# Generated by FakeRAM 2.0
VERSION 5.7 ;
BUSBITCHARS "[]" ;
PROPERTYDEFINITIONS
  MACRO width INTEGER ;
  MACRO depth INTEGER ;
  MACRO banks INTEGER ;
END PROPERTYDEFINITIONS
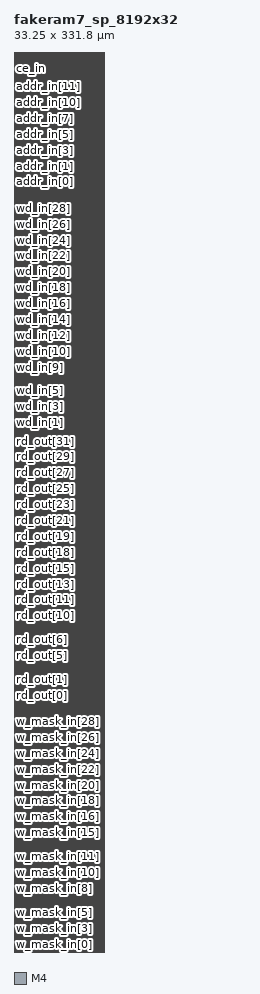
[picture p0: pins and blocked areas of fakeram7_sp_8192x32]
MACRO fakeram7_sp_8192x32
  PROPERTY width 32 ;
  PROPERTY depth 8192 ;
  PROPERTY banks 8 ;
  FOREIGN fakeram7_sp_8192x32 0 0 ;
  SYMMETRY X Y ;
  SIZE 33.250 BY 331.800 ;
  CLASS BLOCK ;
  PIN w_mask_in[0]
    DIRECTION INPUT ;
    USE SIGNAL ;
    SHAPE ABUTMENT ;
    PORT
      LAYER M4 ;
      RECT 0.000 0.048 0.024 0.072 ;
    END
  END w_mask_in[0]
  PIN w_mask_in[1]
    DIRECTION INPUT ;
    USE SIGNAL ;
    SHAPE ABUTMENT ;
    PORT
      LAYER M4 ;
      RECT 0.000 2.976 0.024 3.000 ;
    END
  END w_mask_in[1]
  PIN w_mask_in[2]
    DIRECTION INPUT ;
    USE SIGNAL ;
    SHAPE ABUTMENT ;
    PORT
      LAYER M4 ;
      RECT 0.000 5.904 0.024 5.928 ;
    END
  END w_mask_in[2]
  PIN w_mask_in[3]
    DIRECTION INPUT ;
    USE SIGNAL ;
    SHAPE ABUTMENT ;
    PORT
      LAYER M4 ;
      RECT 0.000 8.832 0.024 8.856 ;
    END
  END w_mask_in[3]
  PIN w_mask_in[4]
    DIRECTION INPUT ;
    USE SIGNAL ;
    SHAPE ABUTMENT ;
    PORT
      LAYER M4 ;
      RECT 0.000 11.760 0.024 11.784 ;
    END
  END w_mask_in[4]
  PIN w_mask_in[5]
    DIRECTION INPUT ;
    USE SIGNAL ;
    SHAPE ABUTMENT ;
    PORT
      LAYER M4 ;
      RECT 0.000 14.688 0.024 14.712 ;
    END
  END w_mask_in[5]
  PIN w_mask_in[6]
    DIRECTION INPUT ;
    USE SIGNAL ;
    SHAPE ABUTMENT ;
    PORT
      LAYER M4 ;
      RECT 0.000 17.616 0.024 17.640 ;
    END
  END w_mask_in[6]
  PIN w_mask_in[7]
    DIRECTION INPUT ;
    USE SIGNAL ;
    SHAPE ABUTMENT ;
    PORT
      LAYER M4 ;
      RECT 0.000 20.544 0.024 20.568 ;
    END
  END w_mask_in[7]
  PIN w_mask_in[8]
    DIRECTION INPUT ;
    USE SIGNAL ;
    SHAPE ABUTMENT ;
    PORT
      LAYER M4 ;
      RECT 0.000 23.472 0.024 23.496 ;
    END
  END w_mask_in[8]
  PIN w_mask_in[9]
    DIRECTION INPUT ;
    USE SIGNAL ;
    SHAPE ABUTMENT ;
    PORT
      LAYER M4 ;
      RECT 0.000 26.400 0.024 26.424 ;
    END
  END w_mask_in[9]
  PIN w_mask_in[10]
    DIRECTION INPUT ;
    USE SIGNAL ;
    SHAPE ABUTMENT ;
    PORT
      LAYER M4 ;
      RECT 0.000 29.328 0.024 29.352 ;
    END
  END w_mask_in[10]
  PIN w_mask_in[11]
    DIRECTION INPUT ;
    USE SIGNAL ;
    SHAPE ABUTMENT ;
    PORT
      LAYER M4 ;
      RECT 0.000 32.256 0.024 32.280 ;
    END
  END w_mask_in[11]
  PIN w_mask_in[12]
    DIRECTION INPUT ;
    USE SIGNAL ;
    SHAPE ABUTMENT ;
    PORT
      LAYER M4 ;
      RECT 0.000 35.184 0.024 35.208 ;
    END
  END w_mask_in[12]
  PIN w_mask_in[13]
    DIRECTION INPUT ;
    USE SIGNAL ;
    SHAPE ABUTMENT ;
    PORT
      LAYER M4 ;
      RECT 0.000 38.112 0.024 38.136 ;
    END
  END w_mask_in[13]
  PIN w_mask_in[14]
    DIRECTION INPUT ;
    USE SIGNAL ;
    SHAPE ABUTMENT ;
    PORT
      LAYER M4 ;
      RECT 0.000 41.040 0.024 41.064 ;
    END
  END w_mask_in[14]
  PIN w_mask_in[15]
    DIRECTION INPUT ;
    USE SIGNAL ;
    SHAPE ABUTMENT ;
    PORT
      LAYER M4 ;
      RECT 0.000 43.968 0.024 43.992 ;
    END
  END w_mask_in[15]
  PIN w_mask_in[16]
    DIRECTION INPUT ;
    USE SIGNAL ;
    SHAPE ABUTMENT ;
    PORT
      LAYER M4 ;
      RECT 0.000 46.896 0.024 46.920 ;
    END
  END w_mask_in[16]
  PIN w_mask_in[17]
    DIRECTION INPUT ;
    USE SIGNAL ;
    SHAPE ABUTMENT ;
    PORT
      LAYER M4 ;
      RECT 0.000 49.824 0.024 49.848 ;
    END
  END w_mask_in[17]
  PIN w_mask_in[18]
    DIRECTION INPUT ;
    USE SIGNAL ;
    SHAPE ABUTMENT ;
    PORT
      LAYER M4 ;
      RECT 0.000 52.752 0.024 52.776 ;
    END
  END w_mask_in[18]
  PIN w_mask_in[19]
    DIRECTION INPUT ;
    USE SIGNAL ;
    SHAPE ABUTMENT ;
    PORT
      LAYER M4 ;
      RECT 0.000 55.680 0.024 55.704 ;
    END
  END w_mask_in[19]
  PIN w_mask_in[20]
    DIRECTION INPUT ;
    USE SIGNAL ;
    SHAPE ABUTMENT ;
    PORT
      LAYER M4 ;
      RECT 0.000 58.608 0.024 58.632 ;
    END
  END w_mask_in[20]
  PIN w_mask_in[21]
    DIRECTION INPUT ;
    USE SIGNAL ;
    SHAPE ABUTMENT ;
    PORT
      LAYER M4 ;
      RECT 0.000 61.536 0.024 61.560 ;
    END
  END w_mask_in[21]
  PIN w_mask_in[22]
    DIRECTION INPUT ;
    USE SIGNAL ;
    SHAPE ABUTMENT ;
    PORT
      LAYER M4 ;
      RECT 0.000 64.464 0.024 64.488 ;
    END
  END w_mask_in[22]
  PIN w_mask_in[23]
    DIRECTION INPUT ;
    USE SIGNAL ;
    SHAPE ABUTMENT ;
    PORT
      LAYER M4 ;
      RECT 0.000 67.392 0.024 67.416 ;
    END
  END w_mask_in[23]
  PIN w_mask_in[24]
    DIRECTION INPUT ;
    USE SIGNAL ;
    SHAPE ABUTMENT ;
    PORT
      LAYER M4 ;
      RECT 0.000 70.320 0.024 70.344 ;
    END
  END w_mask_in[24]
  PIN w_mask_in[25]
    DIRECTION INPUT ;
    USE SIGNAL ;
    SHAPE ABUTMENT ;
    PORT
      LAYER M4 ;
      RECT 0.000 73.248 0.024 73.272 ;
    END
  END w_mask_in[25]
  PIN w_mask_in[26]
    DIRECTION INPUT ;
    USE SIGNAL ;
    SHAPE ABUTMENT ;
    PORT
      LAYER M4 ;
      RECT 0.000 76.176 0.024 76.200 ;
    END
  END w_mask_in[26]
  PIN w_mask_in[27]
    DIRECTION INPUT ;
    USE SIGNAL ;
    SHAPE ABUTMENT ;
    PORT
      LAYER M4 ;
      RECT 0.000 79.104 0.024 79.128 ;
    END
  END w_mask_in[27]
  PIN w_mask_in[28]
    DIRECTION INPUT ;
    USE SIGNAL ;
    SHAPE ABUTMENT ;
    PORT
      LAYER M4 ;
      RECT 0.000 82.032 0.024 82.056 ;
    END
  END w_mask_in[28]
  PIN w_mask_in[29]
    DIRECTION INPUT ;
    USE SIGNAL ;
    SHAPE ABUTMENT ;
    PORT
      LAYER M4 ;
      RECT 0.000 84.960 0.024 84.984 ;
    END
  END w_mask_in[29]
  PIN w_mask_in[30]
    DIRECTION INPUT ;
    USE SIGNAL ;
    SHAPE ABUTMENT ;
    PORT
      LAYER M4 ;
      RECT 0.000 87.888 0.024 87.912 ;
    END
  END w_mask_in[30]
  PIN w_mask_in[31]
    DIRECTION INPUT ;
    USE SIGNAL ;
    SHAPE ABUTMENT ;
    PORT
      LAYER M4 ;
      RECT 0.000 90.816 0.024 90.840 ;
    END
  END w_mask_in[31]
  PIN rd_out[0]
    DIRECTION OUTPUT ;
    USE SIGNAL ;
    SHAPE ABUTMENT ;
    PORT
      LAYER M4 ;
      RECT 0.000 94.656 0.024 94.680 ;
    END
  END rd_out[0]
  PIN rd_out[1]
    DIRECTION OUTPUT ;
    USE SIGNAL ;
    SHAPE ABUTMENT ;
    PORT
      LAYER M4 ;
      RECT 0.000 97.584 0.024 97.608 ;
    END
  END rd_out[1]
  PIN rd_out[2]
    DIRECTION OUTPUT ;
    USE SIGNAL ;
    SHAPE ABUTMENT ;
    PORT
      LAYER M4 ;
      RECT 0.000 100.512 0.024 100.536 ;
    END
  END rd_out[2]
  PIN rd_out[3]
    DIRECTION OUTPUT ;
    USE SIGNAL ;
    SHAPE ABUTMENT ;
    PORT
      LAYER M4 ;
      RECT 0.000 103.440 0.024 103.464 ;
    END
  END rd_out[3]
  PIN rd_out[4]
    DIRECTION OUTPUT ;
    USE SIGNAL ;
    SHAPE ABUTMENT ;
    PORT
      LAYER M4 ;
      RECT 0.000 106.368 0.024 106.392 ;
    END
  END rd_out[4]
  PIN rd_out[5]
    DIRECTION OUTPUT ;
    USE SIGNAL ;
    SHAPE ABUTMENT ;
    PORT
      LAYER M4 ;
      RECT 0.000 109.296 0.024 109.320 ;
    END
  END rd_out[5]
  PIN rd_out[6]
    DIRECTION OUTPUT ;
    USE SIGNAL ;
    SHAPE ABUTMENT ;
    PORT
      LAYER M4 ;
      RECT 0.000 112.224 0.024 112.248 ;
    END
  END rd_out[6]
  PIN rd_out[7]
    DIRECTION OUTPUT ;
    USE SIGNAL ;
    SHAPE ABUTMENT ;
    PORT
      LAYER M4 ;
      RECT 0.000 115.152 0.024 115.176 ;
    END
  END rd_out[7]
  PIN rd_out[8]
    DIRECTION OUTPUT ;
    USE SIGNAL ;
    SHAPE ABUTMENT ;
    PORT
      LAYER M4 ;
      RECT 0.000 118.080 0.024 118.104 ;
    END
  END rd_out[8]
  PIN rd_out[9]
    DIRECTION OUTPUT ;
    USE SIGNAL ;
    SHAPE ABUTMENT ;
    PORT
      LAYER M4 ;
      RECT 0.000 121.008 0.024 121.032 ;
    END
  END rd_out[9]
  PIN rd_out[10]
    DIRECTION OUTPUT ;
    USE SIGNAL ;
    SHAPE ABUTMENT ;
    PORT
      LAYER M4 ;
      RECT 0.000 123.936 0.024 123.960 ;
    END
  END rd_out[10]
  PIN rd_out[11]
    DIRECTION OUTPUT ;
    USE SIGNAL ;
    SHAPE ABUTMENT ;
    PORT
      LAYER M4 ;
      RECT 0.000 126.864 0.024 126.888 ;
    END
  END rd_out[11]
  PIN rd_out[12]
    DIRECTION OUTPUT ;
    USE SIGNAL ;
    SHAPE ABUTMENT ;
    PORT
      LAYER M4 ;
      RECT 0.000 129.792 0.024 129.816 ;
    END
  END rd_out[12]
  PIN rd_out[13]
    DIRECTION OUTPUT ;
    USE SIGNAL ;
    SHAPE ABUTMENT ;
    PORT
      LAYER M4 ;
      RECT 0.000 132.720 0.024 132.744 ;
    END
  END rd_out[13]
  PIN rd_out[14]
    DIRECTION OUTPUT ;
    USE SIGNAL ;
    SHAPE ABUTMENT ;
    PORT
      LAYER M4 ;
      RECT 0.000 135.648 0.024 135.672 ;
    END
  END rd_out[14]
  PIN rd_out[15]
    DIRECTION OUTPUT ;
    USE SIGNAL ;
    SHAPE ABUTMENT ;
    PORT
      LAYER M4 ;
      RECT 0.000 138.576 0.024 138.600 ;
    END
  END rd_out[15]
  PIN rd_out[16]
    DIRECTION OUTPUT ;
    USE SIGNAL ;
    SHAPE ABUTMENT ;
    PORT
      LAYER M4 ;
      RECT 0.000 141.504 0.024 141.528 ;
    END
  END rd_out[16]
  PIN rd_out[17]
    DIRECTION OUTPUT ;
    USE SIGNAL ;
    SHAPE ABUTMENT ;
    PORT
      LAYER M4 ;
      RECT 0.000 144.432 0.024 144.456 ;
    END
  END rd_out[17]
  PIN rd_out[18]
    DIRECTION OUTPUT ;
    USE SIGNAL ;
    SHAPE ABUTMENT ;
    PORT
      LAYER M4 ;
      RECT 0.000 147.360 0.024 147.384 ;
    END
  END rd_out[18]
  PIN rd_out[19]
    DIRECTION OUTPUT ;
    USE SIGNAL ;
    SHAPE ABUTMENT ;
    PORT
      LAYER M4 ;
      RECT 0.000 150.288 0.024 150.312 ;
    END
  END rd_out[19]
  PIN rd_out[20]
    DIRECTION OUTPUT ;
    USE SIGNAL ;
    SHAPE ABUTMENT ;
    PORT
      LAYER M4 ;
      RECT 0.000 153.216 0.024 153.240 ;
    END
  END rd_out[20]
  PIN rd_out[21]
    DIRECTION OUTPUT ;
    USE SIGNAL ;
    SHAPE ABUTMENT ;
    PORT
      LAYER M4 ;
      RECT 0.000 156.144 0.024 156.168 ;
    END
  END rd_out[21]
  PIN rd_out[22]
    DIRECTION OUTPUT ;
    USE SIGNAL ;
    SHAPE ABUTMENT ;
    PORT
      LAYER M4 ;
      RECT 0.000 159.072 0.024 159.096 ;
    END
  END rd_out[22]
  PIN rd_out[23]
    DIRECTION OUTPUT ;
    USE SIGNAL ;
    SHAPE ABUTMENT ;
    PORT
      LAYER M4 ;
      RECT 0.000 162.000 0.024 162.024 ;
    END
  END rd_out[23]
  PIN rd_out[24]
    DIRECTION OUTPUT ;
    USE SIGNAL ;
    SHAPE ABUTMENT ;
    PORT
      LAYER M4 ;
      RECT 0.000 164.928 0.024 164.952 ;
    END
  END rd_out[24]
  PIN rd_out[25]
    DIRECTION OUTPUT ;
    USE SIGNAL ;
    SHAPE ABUTMENT ;
    PORT
      LAYER M4 ;
      RECT 0.000 167.856 0.024 167.880 ;
    END
  END rd_out[25]
  PIN rd_out[26]
    DIRECTION OUTPUT ;
    USE SIGNAL ;
    SHAPE ABUTMENT ;
    PORT
      LAYER M4 ;
      RECT 0.000 170.784 0.024 170.808 ;
    END
  END rd_out[26]
  PIN rd_out[27]
    DIRECTION OUTPUT ;
    USE SIGNAL ;
    SHAPE ABUTMENT ;
    PORT
      LAYER M4 ;
      RECT 0.000 173.712 0.024 173.736 ;
    END
  END rd_out[27]
  PIN rd_out[28]
    DIRECTION OUTPUT ;
    USE SIGNAL ;
    SHAPE ABUTMENT ;
    PORT
      LAYER M4 ;
      RECT 0.000 176.640 0.024 176.664 ;
    END
  END rd_out[28]
  PIN rd_out[29]
    DIRECTION OUTPUT ;
    USE SIGNAL ;
    SHAPE ABUTMENT ;
    PORT
      LAYER M4 ;
      RECT 0.000 179.568 0.024 179.592 ;
    END
  END rd_out[29]
  PIN rd_out[30]
    DIRECTION OUTPUT ;
    USE SIGNAL ;
    SHAPE ABUTMENT ;
    PORT
      LAYER M4 ;
      RECT 0.000 182.496 0.024 182.520 ;
    END
  END rd_out[30]
  PIN rd_out[31]
    DIRECTION OUTPUT ;
    USE SIGNAL ;
    SHAPE ABUTMENT ;
    PORT
      LAYER M4 ;
      RECT 0.000 185.424 0.024 185.448 ;
    END
  END rd_out[31]
  PIN wd_in[0]
    DIRECTION INPUT ;
    USE SIGNAL ;
    SHAPE ABUTMENT ;
    PORT
      LAYER M4 ;
      RECT 0.000 189.264 0.024 189.288 ;
    END
  END wd_in[0]
  PIN wd_in[1]
    DIRECTION INPUT ;
    USE SIGNAL ;
    SHAPE ABUTMENT ;
    PORT
      LAYER M4 ;
      RECT 0.000 192.192 0.024 192.216 ;
    END
  END wd_in[1]
  PIN wd_in[2]
    DIRECTION INPUT ;
    USE SIGNAL ;
    SHAPE ABUTMENT ;
    PORT
      LAYER M4 ;
      RECT 0.000 195.120 0.024 195.144 ;
    END
  END wd_in[2]
  PIN wd_in[3]
    DIRECTION INPUT ;
    USE SIGNAL ;
    SHAPE ABUTMENT ;
    PORT
      LAYER M4 ;
      RECT 0.000 198.048 0.024 198.072 ;
    END
  END wd_in[3]
  PIN wd_in[4]
    DIRECTION INPUT ;
    USE SIGNAL ;
    SHAPE ABUTMENT ;
    PORT
      LAYER M4 ;
      RECT 0.000 200.976 0.024 201.000 ;
    END
  END wd_in[4]
  PIN wd_in[5]
    DIRECTION INPUT ;
    USE SIGNAL ;
    SHAPE ABUTMENT ;
    PORT
      LAYER M4 ;
      RECT 0.000 203.904 0.024 203.928 ;
    END
  END wd_in[5]
  PIN wd_in[6]
    DIRECTION INPUT ;
    USE SIGNAL ;
    SHAPE ABUTMENT ;
    PORT
      LAYER M4 ;
      RECT 0.000 206.832 0.024 206.856 ;
    END
  END wd_in[6]
  PIN wd_in[7]
    DIRECTION INPUT ;
    USE SIGNAL ;
    SHAPE ABUTMENT ;
    PORT
      LAYER M4 ;
      RECT 0.000 209.760 0.024 209.784 ;
    END
  END wd_in[7]
  PIN wd_in[8]
    DIRECTION INPUT ;
    USE SIGNAL ;
    SHAPE ABUTMENT ;
    PORT
      LAYER M4 ;
      RECT 0.000 212.688 0.024 212.712 ;
    END
  END wd_in[8]
  PIN wd_in[9]
    DIRECTION INPUT ;
    USE SIGNAL ;
    SHAPE ABUTMENT ;
    PORT
      LAYER M4 ;
      RECT 0.000 215.616 0.024 215.640 ;
    END
  END wd_in[9]
  PIN wd_in[10]
    DIRECTION INPUT ;
    USE SIGNAL ;
    SHAPE ABUTMENT ;
    PORT
      LAYER M4 ;
      RECT 0.000 218.544 0.024 218.568 ;
    END
  END wd_in[10]
  PIN wd_in[11]
    DIRECTION INPUT ;
    USE SIGNAL ;
    SHAPE ABUTMENT ;
    PORT
      LAYER M4 ;
      RECT 0.000 221.472 0.024 221.496 ;
    END
  END wd_in[11]
  PIN wd_in[12]
    DIRECTION INPUT ;
    USE SIGNAL ;
    SHAPE ABUTMENT ;
    PORT
      LAYER M4 ;
      RECT 0.000 224.400 0.024 224.424 ;
    END
  END wd_in[12]
  PIN wd_in[13]
    DIRECTION INPUT ;
    USE SIGNAL ;
    SHAPE ABUTMENT ;
    PORT
      LAYER M4 ;
      RECT 0.000 227.328 0.024 227.352 ;
    END
  END wd_in[13]
  PIN wd_in[14]
    DIRECTION INPUT ;
    USE SIGNAL ;
    SHAPE ABUTMENT ;
    PORT
      LAYER M4 ;
      RECT 0.000 230.256 0.024 230.280 ;
    END
  END wd_in[14]
  PIN wd_in[15]
    DIRECTION INPUT ;
    USE SIGNAL ;
    SHAPE ABUTMENT ;
    PORT
      LAYER M4 ;
      RECT 0.000 233.184 0.024 233.208 ;
    END
  END wd_in[15]
  PIN wd_in[16]
    DIRECTION INPUT ;
    USE SIGNAL ;
    SHAPE ABUTMENT ;
    PORT
      LAYER M4 ;
      RECT 0.000 236.112 0.024 236.136 ;
    END
  END wd_in[16]
  PIN wd_in[17]
    DIRECTION INPUT ;
    USE SIGNAL ;
    SHAPE ABUTMENT ;
    PORT
      LAYER M4 ;
      RECT 0.000 239.040 0.024 239.064 ;
    END
  END wd_in[17]
  PIN wd_in[18]
    DIRECTION INPUT ;
    USE SIGNAL ;
    SHAPE ABUTMENT ;
    PORT
      LAYER M4 ;
      RECT 0.000 241.968 0.024 241.992 ;
    END
  END wd_in[18]
  PIN wd_in[19]
    DIRECTION INPUT ;
    USE SIGNAL ;
    SHAPE ABUTMENT ;
    PORT
      LAYER M4 ;
      RECT 0.000 244.896 0.024 244.920 ;
    END
  END wd_in[19]
  PIN wd_in[20]
    DIRECTION INPUT ;
    USE SIGNAL ;
    SHAPE ABUTMENT ;
    PORT
      LAYER M4 ;
      RECT 0.000 247.824 0.024 247.848 ;
    END
  END wd_in[20]
  PIN wd_in[21]
    DIRECTION INPUT ;
    USE SIGNAL ;
    SHAPE ABUTMENT ;
    PORT
      LAYER M4 ;
      RECT 0.000 250.752 0.024 250.776 ;
    END
  END wd_in[21]
  PIN wd_in[22]
    DIRECTION INPUT ;
    USE SIGNAL ;
    SHAPE ABUTMENT ;
    PORT
      LAYER M4 ;
      RECT 0.000 253.680 0.024 253.704 ;
    END
  END wd_in[22]
  PIN wd_in[23]
    DIRECTION INPUT ;
    USE SIGNAL ;
    SHAPE ABUTMENT ;
    PORT
      LAYER M4 ;
      RECT 0.000 256.608 0.024 256.632 ;
    END
  END wd_in[23]
  PIN wd_in[24]
    DIRECTION INPUT ;
    USE SIGNAL ;
    SHAPE ABUTMENT ;
    PORT
      LAYER M4 ;
      RECT 0.000 259.536 0.024 259.560 ;
    END
  END wd_in[24]
  PIN wd_in[25]
    DIRECTION INPUT ;
    USE SIGNAL ;
    SHAPE ABUTMENT ;
    PORT
      LAYER M4 ;
      RECT 0.000 262.464 0.024 262.488 ;
    END
  END wd_in[25]
  PIN wd_in[26]
    DIRECTION INPUT ;
    USE SIGNAL ;
    SHAPE ABUTMENT ;
    PORT
      LAYER M4 ;
      RECT 0.000 265.392 0.024 265.416 ;
    END
  END wd_in[26]
  PIN wd_in[27]
    DIRECTION INPUT ;
    USE SIGNAL ;
    SHAPE ABUTMENT ;
    PORT
      LAYER M4 ;
      RECT 0.000 268.320 0.024 268.344 ;
    END
  END wd_in[27]
  PIN wd_in[28]
    DIRECTION INPUT ;
    USE SIGNAL ;
    SHAPE ABUTMENT ;
    PORT
      LAYER M4 ;
      RECT 0.000 271.248 0.024 271.272 ;
    END
  END wd_in[28]
  PIN wd_in[29]
    DIRECTION INPUT ;
    USE SIGNAL ;
    SHAPE ABUTMENT ;
    PORT
      LAYER M4 ;
      RECT 0.000 274.176 0.024 274.200 ;
    END
  END wd_in[29]
  PIN wd_in[30]
    DIRECTION INPUT ;
    USE SIGNAL ;
    SHAPE ABUTMENT ;
    PORT
      LAYER M4 ;
      RECT 0.000 277.104 0.024 277.128 ;
    END
  END wd_in[30]
  PIN wd_in[31]
    DIRECTION INPUT ;
    USE SIGNAL ;
    SHAPE ABUTMENT ;
    PORT
      LAYER M4 ;
      RECT 0.000 280.032 0.024 280.056 ;
    END
  END wd_in[31]
  PIN addr_in[0]
    DIRECTION INPUT ;
    USE SIGNAL ;
    SHAPE ABUTMENT ;
    PORT
      LAYER M4 ;
      RECT 0.000 283.872 0.024 283.896 ;
    END
  END addr_in[0]
  PIN addr_in[1]
    DIRECTION INPUT ;
    USE SIGNAL ;
    SHAPE ABUTMENT ;
    PORT
      LAYER M4 ;
      RECT 0.000 286.800 0.024 286.824 ;
    END
  END addr_in[1]
  PIN addr_in[2]
    DIRECTION INPUT ;
    USE SIGNAL ;
    SHAPE ABUTMENT ;
    PORT
      LAYER M4 ;
      RECT 0.000 289.728 0.024 289.752 ;
    END
  END addr_in[2]
  PIN addr_in[3]
    DIRECTION INPUT ;
    USE SIGNAL ;
    SHAPE ABUTMENT ;
    PORT
      LAYER M4 ;
      RECT 0.000 292.656 0.024 292.680 ;
    END
  END addr_in[3]
  PIN addr_in[4]
    DIRECTION INPUT ;
    USE SIGNAL ;
    SHAPE ABUTMENT ;
    PORT
      LAYER M4 ;
      RECT 0.000 295.584 0.024 295.608 ;
    END
  END addr_in[4]
  PIN addr_in[5]
    DIRECTION INPUT ;
    USE SIGNAL ;
    SHAPE ABUTMENT ;
    PORT
      LAYER M4 ;
      RECT 0.000 298.512 0.024 298.536 ;
    END
  END addr_in[5]
  PIN addr_in[6]
    DIRECTION INPUT ;
    USE SIGNAL ;
    SHAPE ABUTMENT ;
    PORT
      LAYER M4 ;
      RECT 0.000 301.440 0.024 301.464 ;
    END
  END addr_in[6]
  PIN addr_in[7]
    DIRECTION INPUT ;
    USE SIGNAL ;
    SHAPE ABUTMENT ;
    PORT
      LAYER M4 ;
      RECT 0.000 304.368 0.024 304.392 ;
    END
  END addr_in[7]
  PIN addr_in[8]
    DIRECTION INPUT ;
    USE SIGNAL ;
    SHAPE ABUTMENT ;
    PORT
      LAYER M4 ;
      RECT 0.000 307.296 0.024 307.320 ;
    END
  END addr_in[8]
  PIN addr_in[9]
    DIRECTION INPUT ;
    USE SIGNAL ;
    SHAPE ABUTMENT ;
    PORT
      LAYER M4 ;
      RECT 0.000 310.224 0.024 310.248 ;
    END
  END addr_in[9]
  PIN addr_in[10]
    DIRECTION INPUT ;
    USE SIGNAL ;
    SHAPE ABUTMENT ;
    PORT
      LAYER M4 ;
      RECT 0.000 313.152 0.024 313.176 ;
    END
  END addr_in[10]
  PIN addr_in[11]
    DIRECTION INPUT ;
    USE SIGNAL ;
    SHAPE ABUTMENT ;
    PORT
      LAYER M4 ;
      RECT 0.000 316.080 0.024 316.104 ;
    END
  END addr_in[11]
  PIN addr_in[12]
    DIRECTION INPUT ;
    USE SIGNAL ;
    SHAPE ABUTMENT ;
    PORT
      LAYER M4 ;
      RECT 0.000 319.008 0.024 319.032 ;
    END
  END addr_in[12]
  PIN we_in
    DIRECTION INPUT ;
    USE SIGNAL ;
    SHAPE ABUTMENT ;
    PORT
      LAYER M4 ;
      RECT 0.000 322.848 0.024 322.872 ;
    END
  END we_in
  PIN ce_in
    DIRECTION INPUT ;
    USE SIGNAL ;
    SHAPE ABUTMENT ;
    PORT
      LAYER M4 ;
      RECT 0.000 325.776 0.024 325.800 ;
    END
  END ce_in
  PIN clk
    DIRECTION INPUT ;
    USE SIGNAL ;
    SHAPE ABUTMENT ;
    PORT
      LAYER M4 ;
      RECT 0.000 328.704 0.024 328.728 ;
    END
  END clk
  PIN VSS
    DIRECTION INOUT ;
    USE GROUND ;
    PORT
      LAYER M4 ;
      RECT 0.048 0.000 33.202 0.096 ;
      RECT 0.048 0.768 33.202 0.864 ;
      RECT 0.048 1.536 33.202 1.632 ;
      RECT 0.048 2.304 33.202 2.400 ;
      RECT 0.048 3.072 33.202 3.168 ;
      RECT 0.048 3.840 33.202 3.936 ;
      RECT 0.048 4.608 33.202 4.704 ;
      RECT 0.048 5.376 33.202 5.472 ;
      RECT 0.048 6.144 33.202 6.240 ;
      RECT 0.048 6.912 33.202 7.008 ;
      RECT 0.048 7.680 33.202 7.776 ;
      RECT 0.048 8.448 33.202 8.544 ;
      RECT 0.048 9.216 33.202 9.312 ;
      RECT 0.048 9.984 33.202 10.080 ;
      RECT 0.048 10.752 33.202 10.848 ;
      RECT 0.048 11.520 33.202 11.616 ;
      RECT 0.048 12.288 33.202 12.384 ;
      RECT 0.048 13.056 33.202 13.152 ;
      RECT 0.048 13.824 33.202 13.920 ;
      RECT 0.048 14.592 33.202 14.688 ;
      RECT 0.048 15.360 33.202 15.456 ;
      RECT 0.048 16.128 33.202 16.224 ;
      RECT 0.048 16.896 33.202 16.992 ;
      RECT 0.048 17.664 33.202 17.760 ;
      RECT 0.048 18.432 33.202 18.528 ;
      RECT 0.048 19.200 33.202 19.296 ;
      RECT 0.048 19.968 33.202 20.064 ;
      RECT 0.048 20.736 33.202 20.832 ;
      RECT 0.048 21.504 33.202 21.600 ;
      RECT 0.048 22.272 33.202 22.368 ;
      RECT 0.048 23.040 33.202 23.136 ;
      RECT 0.048 23.808 33.202 23.904 ;
      RECT 0.048 24.576 33.202 24.672 ;
      RECT 0.048 25.344 33.202 25.440 ;
      RECT 0.048 26.112 33.202 26.208 ;
      RECT 0.048 26.880 33.202 26.976 ;
      RECT 0.048 27.648 33.202 27.744 ;
      RECT 0.048 28.416 33.202 28.512 ;
      RECT 0.048 29.184 33.202 29.280 ;
      RECT 0.048 29.952 33.202 30.048 ;
      RECT 0.048 30.720 33.202 30.816 ;
      RECT 0.048 31.488 33.202 31.584 ;
      RECT 0.048 32.256 33.202 32.352 ;
      RECT 0.048 33.024 33.202 33.120 ;
      RECT 0.048 33.792 33.202 33.888 ;
      RECT 0.048 34.560 33.202 34.656 ;
      RECT 0.048 35.328 33.202 35.424 ;
      RECT 0.048 36.096 33.202 36.192 ;
      RECT 0.048 36.864 33.202 36.960 ;
      RECT 0.048 37.632 33.202 37.728 ;
      RECT 0.048 38.400 33.202 38.496 ;
      RECT 0.048 39.168 33.202 39.264 ;
      RECT 0.048 39.936 33.202 40.032 ;
      RECT 0.048 40.704 33.202 40.800 ;
      RECT 0.048 41.472 33.202 41.568 ;
      RECT 0.048 42.240 33.202 42.336 ;
      RECT 0.048 43.008 33.202 43.104 ;
      RECT 0.048 43.776 33.202 43.872 ;
      RECT 0.048 44.544 33.202 44.640 ;
      RECT 0.048 45.312 33.202 45.408 ;
      RECT 0.048 46.080 33.202 46.176 ;
      RECT 0.048 46.848 33.202 46.944 ;
      RECT 0.048 47.616 33.202 47.712 ;
      RECT 0.048 48.384 33.202 48.480 ;
      RECT 0.048 49.152 33.202 49.248 ;
      RECT 0.048 49.920 33.202 50.016 ;
      RECT 0.048 50.688 33.202 50.784 ;
      RECT 0.048 51.456 33.202 51.552 ;
      RECT 0.048 52.224 33.202 52.320 ;
      RECT 0.048 52.992 33.202 53.088 ;
      RECT 0.048 53.760 33.202 53.856 ;
      RECT 0.048 54.528 33.202 54.624 ;
      RECT 0.048 55.296 33.202 55.392 ;
      RECT 0.048 56.064 33.202 56.160 ;
      RECT 0.048 56.832 33.202 56.928 ;
      RECT 0.048 57.600 33.202 57.696 ;
      RECT 0.048 58.368 33.202 58.464 ;
      RECT 0.048 59.136 33.202 59.232 ;
      RECT 0.048 59.904 33.202 60.000 ;
      RECT 0.048 60.672 33.202 60.768 ;
      RECT 0.048 61.440 33.202 61.536 ;
      RECT 0.048 62.208 33.202 62.304 ;
      RECT 0.048 62.976 33.202 63.072 ;
      RECT 0.048 63.744 33.202 63.840 ;
      RECT 0.048 64.512 33.202 64.608 ;
      RECT 0.048 65.280 33.202 65.376 ;
      RECT 0.048 66.048 33.202 66.144 ;
      RECT 0.048 66.816 33.202 66.912 ;
      RECT 0.048 67.584 33.202 67.680 ;
      RECT 0.048 68.352 33.202 68.448 ;
      RECT 0.048 69.120 33.202 69.216 ;
      RECT 0.048 69.888 33.202 69.984 ;
      RECT 0.048 70.656 33.202 70.752 ;
      RECT 0.048 71.424 33.202 71.520 ;
      RECT 0.048 72.192 33.202 72.288 ;
      RECT 0.048 72.960 33.202 73.056 ;
      RECT 0.048 73.728 33.202 73.824 ;
      RECT 0.048 74.496 33.202 74.592 ;
      RECT 0.048 75.264 33.202 75.360 ;
      RECT 0.048 76.032 33.202 76.128 ;
      RECT 0.048 76.800 33.202 76.896 ;
      RECT 0.048 77.568 33.202 77.664 ;
      RECT 0.048 78.336 33.202 78.432 ;
      RECT 0.048 79.104 33.202 79.200 ;
      RECT 0.048 79.872 33.202 79.968 ;
      RECT 0.048 80.640 33.202 80.736 ;
      RECT 0.048 81.408 33.202 81.504 ;
      RECT 0.048 82.176 33.202 82.272 ;
      RECT 0.048 82.944 33.202 83.040 ;
      RECT 0.048 83.712 33.202 83.808 ;
      RECT 0.048 84.480 33.202 84.576 ;
      RECT 0.048 85.248 33.202 85.344 ;
      RECT 0.048 86.016 33.202 86.112 ;
      RECT 0.048 86.784 33.202 86.880 ;
      RECT 0.048 87.552 33.202 87.648 ;
      RECT 0.048 88.320 33.202 88.416 ;
      RECT 0.048 89.088 33.202 89.184 ;
      RECT 0.048 89.856 33.202 89.952 ;
      RECT 0.048 90.624 33.202 90.720 ;
      RECT 0.048 91.392 33.202 91.488 ;
      RECT 0.048 92.160 33.202 92.256 ;
      RECT 0.048 92.928 33.202 93.024 ;
      RECT 0.048 93.696 33.202 93.792 ;
      RECT 0.048 94.464 33.202 94.560 ;
      RECT 0.048 95.232 33.202 95.328 ;
      RECT 0.048 96.000 33.202 96.096 ;
      RECT 0.048 96.768 33.202 96.864 ;
      RECT 0.048 97.536 33.202 97.632 ;
      RECT 0.048 98.304 33.202 98.400 ;
      RECT 0.048 99.072 33.202 99.168 ;
      RECT 0.048 99.840 33.202 99.936 ;
      RECT 0.048 100.608 33.202 100.704 ;
      RECT 0.048 101.376 33.202 101.472 ;
      RECT 0.048 102.144 33.202 102.240 ;
      RECT 0.048 102.912 33.202 103.008 ;
      RECT 0.048 103.680 33.202 103.776 ;
      RECT 0.048 104.448 33.202 104.544 ;
      RECT 0.048 105.216 33.202 105.312 ;
      RECT 0.048 105.984 33.202 106.080 ;
      RECT 0.048 106.752 33.202 106.848 ;
      RECT 0.048 107.520 33.202 107.616 ;
      RECT 0.048 108.288 33.202 108.384 ;
      RECT 0.048 109.056 33.202 109.152 ;
      RECT 0.048 109.824 33.202 109.920 ;
      RECT 0.048 110.592 33.202 110.688 ;
      RECT 0.048 111.360 33.202 111.456 ;
      RECT 0.048 112.128 33.202 112.224 ;
      RECT 0.048 112.896 33.202 112.992 ;
      RECT 0.048 113.664 33.202 113.760 ;
      RECT 0.048 114.432 33.202 114.528 ;
      RECT 0.048 115.200 33.202 115.296 ;
      RECT 0.048 115.968 33.202 116.064 ;
      RECT 0.048 116.736 33.202 116.832 ;
      RECT 0.048 117.504 33.202 117.600 ;
      RECT 0.048 118.272 33.202 118.368 ;
      RECT 0.048 119.040 33.202 119.136 ;
      RECT 0.048 119.808 33.202 119.904 ;
      RECT 0.048 120.576 33.202 120.672 ;
      RECT 0.048 121.344 33.202 121.440 ;
      RECT 0.048 122.112 33.202 122.208 ;
      RECT 0.048 122.880 33.202 122.976 ;
      RECT 0.048 123.648 33.202 123.744 ;
      RECT 0.048 124.416 33.202 124.512 ;
      RECT 0.048 125.184 33.202 125.280 ;
      RECT 0.048 125.952 33.202 126.048 ;
      RECT 0.048 126.720 33.202 126.816 ;
      RECT 0.048 127.488 33.202 127.584 ;
      RECT 0.048 128.256 33.202 128.352 ;
      RECT 0.048 129.024 33.202 129.120 ;
      RECT 0.048 129.792 33.202 129.888 ;
      RECT 0.048 130.560 33.202 130.656 ;
      RECT 0.048 131.328 33.202 131.424 ;
      RECT 0.048 132.096 33.202 132.192 ;
      RECT 0.048 132.864 33.202 132.960 ;
      RECT 0.048 133.632 33.202 133.728 ;
      RECT 0.048 134.400 33.202 134.496 ;
      RECT 0.048 135.168 33.202 135.264 ;
      RECT 0.048 135.936 33.202 136.032 ;
      RECT 0.048 136.704 33.202 136.800 ;
      RECT 0.048 137.472 33.202 137.568 ;
      RECT 0.048 138.240 33.202 138.336 ;
      RECT 0.048 139.008 33.202 139.104 ;
      RECT 0.048 139.776 33.202 139.872 ;
      RECT 0.048 140.544 33.202 140.640 ;
      RECT 0.048 141.312 33.202 141.408 ;
      RECT 0.048 142.080 33.202 142.176 ;
      RECT 0.048 142.848 33.202 142.944 ;
      RECT 0.048 143.616 33.202 143.712 ;
      RECT 0.048 144.384 33.202 144.480 ;
      RECT 0.048 145.152 33.202 145.248 ;
      RECT 0.048 145.920 33.202 146.016 ;
      RECT 0.048 146.688 33.202 146.784 ;
      RECT 0.048 147.456 33.202 147.552 ;
      RECT 0.048 148.224 33.202 148.320 ;
      RECT 0.048 148.992 33.202 149.088 ;
      RECT 0.048 149.760 33.202 149.856 ;
      RECT 0.048 150.528 33.202 150.624 ;
      RECT 0.048 151.296 33.202 151.392 ;
      RECT 0.048 152.064 33.202 152.160 ;
      RECT 0.048 152.832 33.202 152.928 ;
      RECT 0.048 153.600 33.202 153.696 ;
      RECT 0.048 154.368 33.202 154.464 ;
      RECT 0.048 155.136 33.202 155.232 ;
      RECT 0.048 155.904 33.202 156.000 ;
      RECT 0.048 156.672 33.202 156.768 ;
      RECT 0.048 157.440 33.202 157.536 ;
      RECT 0.048 158.208 33.202 158.304 ;
      RECT 0.048 158.976 33.202 159.072 ;
      RECT 0.048 159.744 33.202 159.840 ;
      RECT 0.048 160.512 33.202 160.608 ;
      RECT 0.048 161.280 33.202 161.376 ;
      RECT 0.048 162.048 33.202 162.144 ;
      RECT 0.048 162.816 33.202 162.912 ;
      RECT 0.048 163.584 33.202 163.680 ;
      RECT 0.048 164.352 33.202 164.448 ;
      RECT 0.048 165.120 33.202 165.216 ;
      RECT 0.048 165.888 33.202 165.984 ;
      RECT 0.048 166.656 33.202 166.752 ;
      RECT 0.048 167.424 33.202 167.520 ;
      RECT 0.048 168.192 33.202 168.288 ;
      RECT 0.048 168.960 33.202 169.056 ;
      RECT 0.048 169.728 33.202 169.824 ;
      RECT 0.048 170.496 33.202 170.592 ;
      RECT 0.048 171.264 33.202 171.360 ;
      RECT 0.048 172.032 33.202 172.128 ;
      RECT 0.048 172.800 33.202 172.896 ;
      RECT 0.048 173.568 33.202 173.664 ;
      RECT 0.048 174.336 33.202 174.432 ;
      RECT 0.048 175.104 33.202 175.200 ;
      RECT 0.048 175.872 33.202 175.968 ;
      RECT 0.048 176.640 33.202 176.736 ;
      RECT 0.048 177.408 33.202 177.504 ;
      RECT 0.048 178.176 33.202 178.272 ;
      RECT 0.048 178.944 33.202 179.040 ;
      RECT 0.048 179.712 33.202 179.808 ;
      RECT 0.048 180.480 33.202 180.576 ;
      RECT 0.048 181.248 33.202 181.344 ;
      RECT 0.048 182.016 33.202 182.112 ;
      RECT 0.048 182.784 33.202 182.880 ;
      RECT 0.048 183.552 33.202 183.648 ;
      RECT 0.048 184.320 33.202 184.416 ;
      RECT 0.048 185.088 33.202 185.184 ;
      RECT 0.048 185.856 33.202 185.952 ;
      RECT 0.048 186.624 33.202 186.720 ;
      RECT 0.048 187.392 33.202 187.488 ;
      RECT 0.048 188.160 33.202 188.256 ;
      RECT 0.048 188.928 33.202 189.024 ;
      RECT 0.048 189.696 33.202 189.792 ;
      RECT 0.048 190.464 33.202 190.560 ;
      RECT 0.048 191.232 33.202 191.328 ;
      RECT 0.048 192.000 33.202 192.096 ;
      RECT 0.048 192.768 33.202 192.864 ;
      RECT 0.048 193.536 33.202 193.632 ;
      RECT 0.048 194.304 33.202 194.400 ;
      RECT 0.048 195.072 33.202 195.168 ;
      RECT 0.048 195.840 33.202 195.936 ;
      RECT 0.048 196.608 33.202 196.704 ;
      RECT 0.048 197.376 33.202 197.472 ;
      RECT 0.048 198.144 33.202 198.240 ;
      RECT 0.048 198.912 33.202 199.008 ;
      RECT 0.048 199.680 33.202 199.776 ;
      RECT 0.048 200.448 33.202 200.544 ;
      RECT 0.048 201.216 33.202 201.312 ;
      RECT 0.048 201.984 33.202 202.080 ;
      RECT 0.048 202.752 33.202 202.848 ;
      RECT 0.048 203.520 33.202 203.616 ;
      RECT 0.048 204.288 33.202 204.384 ;
      RECT 0.048 205.056 33.202 205.152 ;
      RECT 0.048 205.824 33.202 205.920 ;
      RECT 0.048 206.592 33.202 206.688 ;
      RECT 0.048 207.360 33.202 207.456 ;
      RECT 0.048 208.128 33.202 208.224 ;
      RECT 0.048 208.896 33.202 208.992 ;
      RECT 0.048 209.664 33.202 209.760 ;
      RECT 0.048 210.432 33.202 210.528 ;
      RECT 0.048 211.200 33.202 211.296 ;
      RECT 0.048 211.968 33.202 212.064 ;
      RECT 0.048 212.736 33.202 212.832 ;
      RECT 0.048 213.504 33.202 213.600 ;
      RECT 0.048 214.272 33.202 214.368 ;
      RECT 0.048 215.040 33.202 215.136 ;
      RECT 0.048 215.808 33.202 215.904 ;
      RECT 0.048 216.576 33.202 216.672 ;
      RECT 0.048 217.344 33.202 217.440 ;
      RECT 0.048 218.112 33.202 218.208 ;
      RECT 0.048 218.880 33.202 218.976 ;
      RECT 0.048 219.648 33.202 219.744 ;
      RECT 0.048 220.416 33.202 220.512 ;
      RECT 0.048 221.184 33.202 221.280 ;
      RECT 0.048 221.952 33.202 222.048 ;
      RECT 0.048 222.720 33.202 222.816 ;
      RECT 0.048 223.488 33.202 223.584 ;
      RECT 0.048 224.256 33.202 224.352 ;
      RECT 0.048 225.024 33.202 225.120 ;
      RECT 0.048 225.792 33.202 225.888 ;
      RECT 0.048 226.560 33.202 226.656 ;
      RECT 0.048 227.328 33.202 227.424 ;
      RECT 0.048 228.096 33.202 228.192 ;
      RECT 0.048 228.864 33.202 228.960 ;
      RECT 0.048 229.632 33.202 229.728 ;
      RECT 0.048 230.400 33.202 230.496 ;
      RECT 0.048 231.168 33.202 231.264 ;
      RECT 0.048 231.936 33.202 232.032 ;
      RECT 0.048 232.704 33.202 232.800 ;
      RECT 0.048 233.472 33.202 233.568 ;
      RECT 0.048 234.240 33.202 234.336 ;
      RECT 0.048 235.008 33.202 235.104 ;
      RECT 0.048 235.776 33.202 235.872 ;
      RECT 0.048 236.544 33.202 236.640 ;
      RECT 0.048 237.312 33.202 237.408 ;
      RECT 0.048 238.080 33.202 238.176 ;
      RECT 0.048 238.848 33.202 238.944 ;
      RECT 0.048 239.616 33.202 239.712 ;
      RECT 0.048 240.384 33.202 240.480 ;
      RECT 0.048 241.152 33.202 241.248 ;
      RECT 0.048 241.920 33.202 242.016 ;
      RECT 0.048 242.688 33.202 242.784 ;
      RECT 0.048 243.456 33.202 243.552 ;
      RECT 0.048 244.224 33.202 244.320 ;
      RECT 0.048 244.992 33.202 245.088 ;
      RECT 0.048 245.760 33.202 245.856 ;
      RECT 0.048 246.528 33.202 246.624 ;
      RECT 0.048 247.296 33.202 247.392 ;
      RECT 0.048 248.064 33.202 248.160 ;
      RECT 0.048 248.832 33.202 248.928 ;
      RECT 0.048 249.600 33.202 249.696 ;
      RECT 0.048 250.368 33.202 250.464 ;
      RECT 0.048 251.136 33.202 251.232 ;
      RECT 0.048 251.904 33.202 252.000 ;
      RECT 0.048 252.672 33.202 252.768 ;
      RECT 0.048 253.440 33.202 253.536 ;
      RECT 0.048 254.208 33.202 254.304 ;
      RECT 0.048 254.976 33.202 255.072 ;
      RECT 0.048 255.744 33.202 255.840 ;
      RECT 0.048 256.512 33.202 256.608 ;
      RECT 0.048 257.280 33.202 257.376 ;
      RECT 0.048 258.048 33.202 258.144 ;
      RECT 0.048 258.816 33.202 258.912 ;
      RECT 0.048 259.584 33.202 259.680 ;
      RECT 0.048 260.352 33.202 260.448 ;
      RECT 0.048 261.120 33.202 261.216 ;
      RECT 0.048 261.888 33.202 261.984 ;
      RECT 0.048 262.656 33.202 262.752 ;
      RECT 0.048 263.424 33.202 263.520 ;
      RECT 0.048 264.192 33.202 264.288 ;
      RECT 0.048 264.960 33.202 265.056 ;
      RECT 0.048 265.728 33.202 265.824 ;
      RECT 0.048 266.496 33.202 266.592 ;
      RECT 0.048 267.264 33.202 267.360 ;
      RECT 0.048 268.032 33.202 268.128 ;
      RECT 0.048 268.800 33.202 268.896 ;
      RECT 0.048 269.568 33.202 269.664 ;
      RECT 0.048 270.336 33.202 270.432 ;
      RECT 0.048 271.104 33.202 271.200 ;
      RECT 0.048 271.872 33.202 271.968 ;
      RECT 0.048 272.640 33.202 272.736 ;
      RECT 0.048 273.408 33.202 273.504 ;
      RECT 0.048 274.176 33.202 274.272 ;
      RECT 0.048 274.944 33.202 275.040 ;
      RECT 0.048 275.712 33.202 275.808 ;
      RECT 0.048 276.480 33.202 276.576 ;
      RECT 0.048 277.248 33.202 277.344 ;
      RECT 0.048 278.016 33.202 278.112 ;
      RECT 0.048 278.784 33.202 278.880 ;
      RECT 0.048 279.552 33.202 279.648 ;
      RECT 0.048 280.320 33.202 280.416 ;
      RECT 0.048 281.088 33.202 281.184 ;
      RECT 0.048 281.856 33.202 281.952 ;
      RECT 0.048 282.624 33.202 282.720 ;
      RECT 0.048 283.392 33.202 283.488 ;
      RECT 0.048 284.160 33.202 284.256 ;
      RECT 0.048 284.928 33.202 285.024 ;
      RECT 0.048 285.696 33.202 285.792 ;
      RECT 0.048 286.464 33.202 286.560 ;
      RECT 0.048 287.232 33.202 287.328 ;
      RECT 0.048 288.000 33.202 288.096 ;
      RECT 0.048 288.768 33.202 288.864 ;
      RECT 0.048 289.536 33.202 289.632 ;
      RECT 0.048 290.304 33.202 290.400 ;
      RECT 0.048 291.072 33.202 291.168 ;
      RECT 0.048 291.840 33.202 291.936 ;
      RECT 0.048 292.608 33.202 292.704 ;
      RECT 0.048 293.376 33.202 293.472 ;
      RECT 0.048 294.144 33.202 294.240 ;
      RECT 0.048 294.912 33.202 295.008 ;
      RECT 0.048 295.680 33.202 295.776 ;
      RECT 0.048 296.448 33.202 296.544 ;
      RECT 0.048 297.216 33.202 297.312 ;
      RECT 0.048 297.984 33.202 298.080 ;
      RECT 0.048 298.752 33.202 298.848 ;
      RECT 0.048 299.520 33.202 299.616 ;
      RECT 0.048 300.288 33.202 300.384 ;
      RECT 0.048 301.056 33.202 301.152 ;
      RECT 0.048 301.824 33.202 301.920 ;
      RECT 0.048 302.592 33.202 302.688 ;
      RECT 0.048 303.360 33.202 303.456 ;
      RECT 0.048 304.128 33.202 304.224 ;
      RECT 0.048 304.896 33.202 304.992 ;
      RECT 0.048 305.664 33.202 305.760 ;
      RECT 0.048 306.432 33.202 306.528 ;
      RECT 0.048 307.200 33.202 307.296 ;
      RECT 0.048 307.968 33.202 308.064 ;
      RECT 0.048 308.736 33.202 308.832 ;
      RECT 0.048 309.504 33.202 309.600 ;
      RECT 0.048 310.272 33.202 310.368 ;
      RECT 0.048 311.040 33.202 311.136 ;
      RECT 0.048 311.808 33.202 311.904 ;
      RECT 0.048 312.576 33.202 312.672 ;
      RECT 0.048 313.344 33.202 313.440 ;
      RECT 0.048 314.112 33.202 314.208 ;
      RECT 0.048 314.880 33.202 314.976 ;
      RECT 0.048 315.648 33.202 315.744 ;
      RECT 0.048 316.416 33.202 316.512 ;
      RECT 0.048 317.184 33.202 317.280 ;
      RECT 0.048 317.952 33.202 318.048 ;
      RECT 0.048 318.720 33.202 318.816 ;
      RECT 0.048 319.488 33.202 319.584 ;
      RECT 0.048 320.256 33.202 320.352 ;
      RECT 0.048 321.024 33.202 321.120 ;
      RECT 0.048 321.792 33.202 321.888 ;
      RECT 0.048 322.560 33.202 322.656 ;
      RECT 0.048 323.328 33.202 323.424 ;
      RECT 0.048 324.096 33.202 324.192 ;
      RECT 0.048 324.864 33.202 324.960 ;
      RECT 0.048 325.632 33.202 325.728 ;
      RECT 0.048 326.400 33.202 326.496 ;
      RECT 0.048 327.168 33.202 327.264 ;
      RECT 0.048 327.936 33.202 328.032 ;
      RECT 0.048 328.704 33.202 328.800 ;
      RECT 0.048 329.472 33.202 329.568 ;
      RECT 0.048 330.240 33.202 330.336 ;
      RECT 0.048 331.008 33.202 331.104 ;
    END
  END VSS
  PIN VDD
    DIRECTION INOUT ;
    USE POWER ;
    PORT
      LAYER M4 ;
      RECT 0.048 0.384 33.202 0.480 ;
      RECT 0.048 1.152 33.202 1.248 ;
      RECT 0.048 1.920 33.202 2.016 ;
      RECT 0.048 2.688 33.202 2.784 ;
      RECT 0.048 3.456 33.202 3.552 ;
      RECT 0.048 4.224 33.202 4.320 ;
      RECT 0.048 4.992 33.202 5.088 ;
      RECT 0.048 5.760 33.202 5.856 ;
      RECT 0.048 6.528 33.202 6.624 ;
      RECT 0.048 7.296 33.202 7.392 ;
      RECT 0.048 8.064 33.202 8.160 ;
      RECT 0.048 8.832 33.202 8.928 ;
      RECT 0.048 9.600 33.202 9.696 ;
      RECT 0.048 10.368 33.202 10.464 ;
      RECT 0.048 11.136 33.202 11.232 ;
      RECT 0.048 11.904 33.202 12.000 ;
      RECT 0.048 12.672 33.202 12.768 ;
      RECT 0.048 13.440 33.202 13.536 ;
      RECT 0.048 14.208 33.202 14.304 ;
      RECT 0.048 14.976 33.202 15.072 ;
      RECT 0.048 15.744 33.202 15.840 ;
      RECT 0.048 16.512 33.202 16.608 ;
      RECT 0.048 17.280 33.202 17.376 ;
      RECT 0.048 18.048 33.202 18.144 ;
      RECT 0.048 18.816 33.202 18.912 ;
      RECT 0.048 19.584 33.202 19.680 ;
      RECT 0.048 20.352 33.202 20.448 ;
      RECT 0.048 21.120 33.202 21.216 ;
      RECT 0.048 21.888 33.202 21.984 ;
      RECT 0.048 22.656 33.202 22.752 ;
      RECT 0.048 23.424 33.202 23.520 ;
      RECT 0.048 24.192 33.202 24.288 ;
      RECT 0.048 24.960 33.202 25.056 ;
      RECT 0.048 25.728 33.202 25.824 ;
      RECT 0.048 26.496 33.202 26.592 ;
      RECT 0.048 27.264 33.202 27.360 ;
      RECT 0.048 28.032 33.202 28.128 ;
      RECT 0.048 28.800 33.202 28.896 ;
      RECT 0.048 29.568 33.202 29.664 ;
      RECT 0.048 30.336 33.202 30.432 ;
      RECT 0.048 31.104 33.202 31.200 ;
      RECT 0.048 31.872 33.202 31.968 ;
      RECT 0.048 32.640 33.202 32.736 ;
      RECT 0.048 33.408 33.202 33.504 ;
      RECT 0.048 34.176 33.202 34.272 ;
      RECT 0.048 34.944 33.202 35.040 ;
      RECT 0.048 35.712 33.202 35.808 ;
      RECT 0.048 36.480 33.202 36.576 ;
      RECT 0.048 37.248 33.202 37.344 ;
      RECT 0.048 38.016 33.202 38.112 ;
      RECT 0.048 38.784 33.202 38.880 ;
      RECT 0.048 39.552 33.202 39.648 ;
      RECT 0.048 40.320 33.202 40.416 ;
      RECT 0.048 41.088 33.202 41.184 ;
      RECT 0.048 41.856 33.202 41.952 ;
      RECT 0.048 42.624 33.202 42.720 ;
      RECT 0.048 43.392 33.202 43.488 ;
      RECT 0.048 44.160 33.202 44.256 ;
      RECT 0.048 44.928 33.202 45.024 ;
      RECT 0.048 45.696 33.202 45.792 ;
      RECT 0.048 46.464 33.202 46.560 ;
      RECT 0.048 47.232 33.202 47.328 ;
      RECT 0.048 48.000 33.202 48.096 ;
      RECT 0.048 48.768 33.202 48.864 ;
      RECT 0.048 49.536 33.202 49.632 ;
      RECT 0.048 50.304 33.202 50.400 ;
      RECT 0.048 51.072 33.202 51.168 ;
      RECT 0.048 51.840 33.202 51.936 ;
      RECT 0.048 52.608 33.202 52.704 ;
      RECT 0.048 53.376 33.202 53.472 ;
      RECT 0.048 54.144 33.202 54.240 ;
      RECT 0.048 54.912 33.202 55.008 ;
      RECT 0.048 55.680 33.202 55.776 ;
      RECT 0.048 56.448 33.202 56.544 ;
      RECT 0.048 57.216 33.202 57.312 ;
      RECT 0.048 57.984 33.202 58.080 ;
      RECT 0.048 58.752 33.202 58.848 ;
      RECT 0.048 59.520 33.202 59.616 ;
      RECT 0.048 60.288 33.202 60.384 ;
      RECT 0.048 61.056 33.202 61.152 ;
      RECT 0.048 61.824 33.202 61.920 ;
      RECT 0.048 62.592 33.202 62.688 ;
      RECT 0.048 63.360 33.202 63.456 ;
      RECT 0.048 64.128 33.202 64.224 ;
      RECT 0.048 64.896 33.202 64.992 ;
      RECT 0.048 65.664 33.202 65.760 ;
      RECT 0.048 66.432 33.202 66.528 ;
      RECT 0.048 67.200 33.202 67.296 ;
      RECT 0.048 67.968 33.202 68.064 ;
      RECT 0.048 68.736 33.202 68.832 ;
      RECT 0.048 69.504 33.202 69.600 ;
      RECT 0.048 70.272 33.202 70.368 ;
      RECT 0.048 71.040 33.202 71.136 ;
      RECT 0.048 71.808 33.202 71.904 ;
      RECT 0.048 72.576 33.202 72.672 ;
      RECT 0.048 73.344 33.202 73.440 ;
      RECT 0.048 74.112 33.202 74.208 ;
      RECT 0.048 74.880 33.202 74.976 ;
      RECT 0.048 75.648 33.202 75.744 ;
      RECT 0.048 76.416 33.202 76.512 ;
      RECT 0.048 77.184 33.202 77.280 ;
      RECT 0.048 77.952 33.202 78.048 ;
      RECT 0.048 78.720 33.202 78.816 ;
      RECT 0.048 79.488 33.202 79.584 ;
      RECT 0.048 80.256 33.202 80.352 ;
      RECT 0.048 81.024 33.202 81.120 ;
      RECT 0.048 81.792 33.202 81.888 ;
      RECT 0.048 82.560 33.202 82.656 ;
      RECT 0.048 83.328 33.202 83.424 ;
      RECT 0.048 84.096 33.202 84.192 ;
      RECT 0.048 84.864 33.202 84.960 ;
      RECT 0.048 85.632 33.202 85.728 ;
      RECT 0.048 86.400 33.202 86.496 ;
      RECT 0.048 87.168 33.202 87.264 ;
      RECT 0.048 87.936 33.202 88.032 ;
      RECT 0.048 88.704 33.202 88.800 ;
      RECT 0.048 89.472 33.202 89.568 ;
      RECT 0.048 90.240 33.202 90.336 ;
      RECT 0.048 91.008 33.202 91.104 ;
      RECT 0.048 91.776 33.202 91.872 ;
      RECT 0.048 92.544 33.202 92.640 ;
      RECT 0.048 93.312 33.202 93.408 ;
      RECT 0.048 94.080 33.202 94.176 ;
      RECT 0.048 94.848 33.202 94.944 ;
      RECT 0.048 95.616 33.202 95.712 ;
      RECT 0.048 96.384 33.202 96.480 ;
      RECT 0.048 97.152 33.202 97.248 ;
      RECT 0.048 97.920 33.202 98.016 ;
      RECT 0.048 98.688 33.202 98.784 ;
      RECT 0.048 99.456 33.202 99.552 ;
      RECT 0.048 100.224 33.202 100.320 ;
      RECT 0.048 100.992 33.202 101.088 ;
      RECT 0.048 101.760 33.202 101.856 ;
      RECT 0.048 102.528 33.202 102.624 ;
      RECT 0.048 103.296 33.202 103.392 ;
      RECT 0.048 104.064 33.202 104.160 ;
      RECT 0.048 104.832 33.202 104.928 ;
      RECT 0.048 105.600 33.202 105.696 ;
      RECT 0.048 106.368 33.202 106.464 ;
      RECT 0.048 107.136 33.202 107.232 ;
      RECT 0.048 107.904 33.202 108.000 ;
      RECT 0.048 108.672 33.202 108.768 ;
      RECT 0.048 109.440 33.202 109.536 ;
      RECT 0.048 110.208 33.202 110.304 ;
      RECT 0.048 110.976 33.202 111.072 ;
      RECT 0.048 111.744 33.202 111.840 ;
      RECT 0.048 112.512 33.202 112.608 ;
      RECT 0.048 113.280 33.202 113.376 ;
      RECT 0.048 114.048 33.202 114.144 ;
      RECT 0.048 114.816 33.202 114.912 ;
      RECT 0.048 115.584 33.202 115.680 ;
      RECT 0.048 116.352 33.202 116.448 ;
      RECT 0.048 117.120 33.202 117.216 ;
      RECT 0.048 117.888 33.202 117.984 ;
      RECT 0.048 118.656 33.202 118.752 ;
      RECT 0.048 119.424 33.202 119.520 ;
      RECT 0.048 120.192 33.202 120.288 ;
      RECT 0.048 120.960 33.202 121.056 ;
      RECT 0.048 121.728 33.202 121.824 ;
      RECT 0.048 122.496 33.202 122.592 ;
      RECT 0.048 123.264 33.202 123.360 ;
      RECT 0.048 124.032 33.202 124.128 ;
      RECT 0.048 124.800 33.202 124.896 ;
      RECT 0.048 125.568 33.202 125.664 ;
      RECT 0.048 126.336 33.202 126.432 ;
      RECT 0.048 127.104 33.202 127.200 ;
      RECT 0.048 127.872 33.202 127.968 ;
      RECT 0.048 128.640 33.202 128.736 ;
      RECT 0.048 129.408 33.202 129.504 ;
      RECT 0.048 130.176 33.202 130.272 ;
      RECT 0.048 130.944 33.202 131.040 ;
      RECT 0.048 131.712 33.202 131.808 ;
      RECT 0.048 132.480 33.202 132.576 ;
      RECT 0.048 133.248 33.202 133.344 ;
      RECT 0.048 134.016 33.202 134.112 ;
      RECT 0.048 134.784 33.202 134.880 ;
      RECT 0.048 135.552 33.202 135.648 ;
      RECT 0.048 136.320 33.202 136.416 ;
      RECT 0.048 137.088 33.202 137.184 ;
      RECT 0.048 137.856 33.202 137.952 ;
      RECT 0.048 138.624 33.202 138.720 ;
      RECT 0.048 139.392 33.202 139.488 ;
      RECT 0.048 140.160 33.202 140.256 ;
      RECT 0.048 140.928 33.202 141.024 ;
      RECT 0.048 141.696 33.202 141.792 ;
      RECT 0.048 142.464 33.202 142.560 ;
      RECT 0.048 143.232 33.202 143.328 ;
      RECT 0.048 144.000 33.202 144.096 ;
      RECT 0.048 144.768 33.202 144.864 ;
      RECT 0.048 145.536 33.202 145.632 ;
      RECT 0.048 146.304 33.202 146.400 ;
      RECT 0.048 147.072 33.202 147.168 ;
      RECT 0.048 147.840 33.202 147.936 ;
      RECT 0.048 148.608 33.202 148.704 ;
      RECT 0.048 149.376 33.202 149.472 ;
      RECT 0.048 150.144 33.202 150.240 ;
      RECT 0.048 150.912 33.202 151.008 ;
      RECT 0.048 151.680 33.202 151.776 ;
      RECT 0.048 152.448 33.202 152.544 ;
      RECT 0.048 153.216 33.202 153.312 ;
      RECT 0.048 153.984 33.202 154.080 ;
      RECT 0.048 154.752 33.202 154.848 ;
      RECT 0.048 155.520 33.202 155.616 ;
      RECT 0.048 156.288 33.202 156.384 ;
      RECT 0.048 157.056 33.202 157.152 ;
      RECT 0.048 157.824 33.202 157.920 ;
      RECT 0.048 158.592 33.202 158.688 ;
      RECT 0.048 159.360 33.202 159.456 ;
      RECT 0.048 160.128 33.202 160.224 ;
      RECT 0.048 160.896 33.202 160.992 ;
      RECT 0.048 161.664 33.202 161.760 ;
      RECT 0.048 162.432 33.202 162.528 ;
      RECT 0.048 163.200 33.202 163.296 ;
      RECT 0.048 163.968 33.202 164.064 ;
      RECT 0.048 164.736 33.202 164.832 ;
      RECT 0.048 165.504 33.202 165.600 ;
      RECT 0.048 166.272 33.202 166.368 ;
      RECT 0.048 167.040 33.202 167.136 ;
      RECT 0.048 167.808 33.202 167.904 ;
      RECT 0.048 168.576 33.202 168.672 ;
      RECT 0.048 169.344 33.202 169.440 ;
      RECT 0.048 170.112 33.202 170.208 ;
      RECT 0.048 170.880 33.202 170.976 ;
      RECT 0.048 171.648 33.202 171.744 ;
      RECT 0.048 172.416 33.202 172.512 ;
      RECT 0.048 173.184 33.202 173.280 ;
      RECT 0.048 173.952 33.202 174.048 ;
      RECT 0.048 174.720 33.202 174.816 ;
      RECT 0.048 175.488 33.202 175.584 ;
      RECT 0.048 176.256 33.202 176.352 ;
      RECT 0.048 177.024 33.202 177.120 ;
      RECT 0.048 177.792 33.202 177.888 ;
      RECT 0.048 178.560 33.202 178.656 ;
      RECT 0.048 179.328 33.202 179.424 ;
      RECT 0.048 180.096 33.202 180.192 ;
      RECT 0.048 180.864 33.202 180.960 ;
      RECT 0.048 181.632 33.202 181.728 ;
      RECT 0.048 182.400 33.202 182.496 ;
      RECT 0.048 183.168 33.202 183.264 ;
      RECT 0.048 183.936 33.202 184.032 ;
      RECT 0.048 184.704 33.202 184.800 ;
      RECT 0.048 185.472 33.202 185.568 ;
      RECT 0.048 186.240 33.202 186.336 ;
      RECT 0.048 187.008 33.202 187.104 ;
      RECT 0.048 187.776 33.202 187.872 ;
      RECT 0.048 188.544 33.202 188.640 ;
      RECT 0.048 189.312 33.202 189.408 ;
      RECT 0.048 190.080 33.202 190.176 ;
      RECT 0.048 190.848 33.202 190.944 ;
      RECT 0.048 191.616 33.202 191.712 ;
      RECT 0.048 192.384 33.202 192.480 ;
      RECT 0.048 193.152 33.202 193.248 ;
      RECT 0.048 193.920 33.202 194.016 ;
      RECT 0.048 194.688 33.202 194.784 ;
      RECT 0.048 195.456 33.202 195.552 ;
      RECT 0.048 196.224 33.202 196.320 ;
      RECT 0.048 196.992 33.202 197.088 ;
      RECT 0.048 197.760 33.202 197.856 ;
      RECT 0.048 198.528 33.202 198.624 ;
      RECT 0.048 199.296 33.202 199.392 ;
      RECT 0.048 200.064 33.202 200.160 ;
      RECT 0.048 200.832 33.202 200.928 ;
      RECT 0.048 201.600 33.202 201.696 ;
      RECT 0.048 202.368 33.202 202.464 ;
      RECT 0.048 203.136 33.202 203.232 ;
      RECT 0.048 203.904 33.202 204.000 ;
      RECT 0.048 204.672 33.202 204.768 ;
      RECT 0.048 205.440 33.202 205.536 ;
      RECT 0.048 206.208 33.202 206.304 ;
      RECT 0.048 206.976 33.202 207.072 ;
      RECT 0.048 207.744 33.202 207.840 ;
      RECT 0.048 208.512 33.202 208.608 ;
      RECT 0.048 209.280 33.202 209.376 ;
      RECT 0.048 210.048 33.202 210.144 ;
      RECT 0.048 210.816 33.202 210.912 ;
      RECT 0.048 211.584 33.202 211.680 ;
      RECT 0.048 212.352 33.202 212.448 ;
      RECT 0.048 213.120 33.202 213.216 ;
      RECT 0.048 213.888 33.202 213.984 ;
      RECT 0.048 214.656 33.202 214.752 ;
      RECT 0.048 215.424 33.202 215.520 ;
      RECT 0.048 216.192 33.202 216.288 ;
      RECT 0.048 216.960 33.202 217.056 ;
      RECT 0.048 217.728 33.202 217.824 ;
      RECT 0.048 218.496 33.202 218.592 ;
      RECT 0.048 219.264 33.202 219.360 ;
      RECT 0.048 220.032 33.202 220.128 ;
      RECT 0.048 220.800 33.202 220.896 ;
      RECT 0.048 221.568 33.202 221.664 ;
      RECT 0.048 222.336 33.202 222.432 ;
      RECT 0.048 223.104 33.202 223.200 ;
      RECT 0.048 223.872 33.202 223.968 ;
      RECT 0.048 224.640 33.202 224.736 ;
      RECT 0.048 225.408 33.202 225.504 ;
      RECT 0.048 226.176 33.202 226.272 ;
      RECT 0.048 226.944 33.202 227.040 ;
      RECT 0.048 227.712 33.202 227.808 ;
      RECT 0.048 228.480 33.202 228.576 ;
      RECT 0.048 229.248 33.202 229.344 ;
      RECT 0.048 230.016 33.202 230.112 ;
      RECT 0.048 230.784 33.202 230.880 ;
      RECT 0.048 231.552 33.202 231.648 ;
      RECT 0.048 232.320 33.202 232.416 ;
      RECT 0.048 233.088 33.202 233.184 ;
      RECT 0.048 233.856 33.202 233.952 ;
      RECT 0.048 234.624 33.202 234.720 ;
      RECT 0.048 235.392 33.202 235.488 ;
      RECT 0.048 236.160 33.202 236.256 ;
      RECT 0.048 236.928 33.202 237.024 ;
      RECT 0.048 237.696 33.202 237.792 ;
      RECT 0.048 238.464 33.202 238.560 ;
      RECT 0.048 239.232 33.202 239.328 ;
      RECT 0.048 240.000 33.202 240.096 ;
      RECT 0.048 240.768 33.202 240.864 ;
      RECT 0.048 241.536 33.202 241.632 ;
      RECT 0.048 242.304 33.202 242.400 ;
      RECT 0.048 243.072 33.202 243.168 ;
      RECT 0.048 243.840 33.202 243.936 ;
      RECT 0.048 244.608 33.202 244.704 ;
      RECT 0.048 245.376 33.202 245.472 ;
      RECT 0.048 246.144 33.202 246.240 ;
      RECT 0.048 246.912 33.202 247.008 ;
      RECT 0.048 247.680 33.202 247.776 ;
      RECT 0.048 248.448 33.202 248.544 ;
      RECT 0.048 249.216 33.202 249.312 ;
      RECT 0.048 249.984 33.202 250.080 ;
      RECT 0.048 250.752 33.202 250.848 ;
      RECT 0.048 251.520 33.202 251.616 ;
      RECT 0.048 252.288 33.202 252.384 ;
      RECT 0.048 253.056 33.202 253.152 ;
      RECT 0.048 253.824 33.202 253.920 ;
      RECT 0.048 254.592 33.202 254.688 ;
      RECT 0.048 255.360 33.202 255.456 ;
      RECT 0.048 256.128 33.202 256.224 ;
      RECT 0.048 256.896 33.202 256.992 ;
      RECT 0.048 257.664 33.202 257.760 ;
      RECT 0.048 258.432 33.202 258.528 ;
      RECT 0.048 259.200 33.202 259.296 ;
      RECT 0.048 259.968 33.202 260.064 ;
      RECT 0.048 260.736 33.202 260.832 ;
      RECT 0.048 261.504 33.202 261.600 ;
      RECT 0.048 262.272 33.202 262.368 ;
      RECT 0.048 263.040 33.202 263.136 ;
      RECT 0.048 263.808 33.202 263.904 ;
      RECT 0.048 264.576 33.202 264.672 ;
      RECT 0.048 265.344 33.202 265.440 ;
      RECT 0.048 266.112 33.202 266.208 ;
      RECT 0.048 266.880 33.202 266.976 ;
      RECT 0.048 267.648 33.202 267.744 ;
      RECT 0.048 268.416 33.202 268.512 ;
      RECT 0.048 269.184 33.202 269.280 ;
      RECT 0.048 269.952 33.202 270.048 ;
      RECT 0.048 270.720 33.202 270.816 ;
      RECT 0.048 271.488 33.202 271.584 ;
      RECT 0.048 272.256 33.202 272.352 ;
      RECT 0.048 273.024 33.202 273.120 ;
      RECT 0.048 273.792 33.202 273.888 ;
      RECT 0.048 274.560 33.202 274.656 ;
      RECT 0.048 275.328 33.202 275.424 ;
      RECT 0.048 276.096 33.202 276.192 ;
      RECT 0.048 276.864 33.202 276.960 ;
      RECT 0.048 277.632 33.202 277.728 ;
      RECT 0.048 278.400 33.202 278.496 ;
      RECT 0.048 279.168 33.202 279.264 ;
      RECT 0.048 279.936 33.202 280.032 ;
      RECT 0.048 280.704 33.202 280.800 ;
      RECT 0.048 281.472 33.202 281.568 ;
      RECT 0.048 282.240 33.202 282.336 ;
      RECT 0.048 283.008 33.202 283.104 ;
      RECT 0.048 283.776 33.202 283.872 ;
      RECT 0.048 284.544 33.202 284.640 ;
      RECT 0.048 285.312 33.202 285.408 ;
      RECT 0.048 286.080 33.202 286.176 ;
      RECT 0.048 286.848 33.202 286.944 ;
      RECT 0.048 287.616 33.202 287.712 ;
      RECT 0.048 288.384 33.202 288.480 ;
      RECT 0.048 289.152 33.202 289.248 ;
      RECT 0.048 289.920 33.202 290.016 ;
      RECT 0.048 290.688 33.202 290.784 ;
      RECT 0.048 291.456 33.202 291.552 ;
      RECT 0.048 292.224 33.202 292.320 ;
      RECT 0.048 292.992 33.202 293.088 ;
      RECT 0.048 293.760 33.202 293.856 ;
      RECT 0.048 294.528 33.202 294.624 ;
      RECT 0.048 295.296 33.202 295.392 ;
      RECT 0.048 296.064 33.202 296.160 ;
      RECT 0.048 296.832 33.202 296.928 ;
      RECT 0.048 297.600 33.202 297.696 ;
      RECT 0.048 298.368 33.202 298.464 ;
      RECT 0.048 299.136 33.202 299.232 ;
      RECT 0.048 299.904 33.202 300.000 ;
      RECT 0.048 300.672 33.202 300.768 ;
      RECT 0.048 301.440 33.202 301.536 ;
      RECT 0.048 302.208 33.202 302.304 ;
      RECT 0.048 302.976 33.202 303.072 ;
      RECT 0.048 303.744 33.202 303.840 ;
      RECT 0.048 304.512 33.202 304.608 ;
      RECT 0.048 305.280 33.202 305.376 ;
      RECT 0.048 306.048 33.202 306.144 ;
      RECT 0.048 306.816 33.202 306.912 ;
      RECT 0.048 307.584 33.202 307.680 ;
      RECT 0.048 308.352 33.202 308.448 ;
      RECT 0.048 309.120 33.202 309.216 ;
      RECT 0.048 309.888 33.202 309.984 ;
      RECT 0.048 310.656 33.202 310.752 ;
      RECT 0.048 311.424 33.202 311.520 ;
      RECT 0.048 312.192 33.202 312.288 ;
      RECT 0.048 312.960 33.202 313.056 ;
      RECT 0.048 313.728 33.202 313.824 ;
      RECT 0.048 314.496 33.202 314.592 ;
      RECT 0.048 315.264 33.202 315.360 ;
      RECT 0.048 316.032 33.202 316.128 ;
      RECT 0.048 316.800 33.202 316.896 ;
      RECT 0.048 317.568 33.202 317.664 ;
      RECT 0.048 318.336 33.202 318.432 ;
      RECT 0.048 319.104 33.202 319.200 ;
      RECT 0.048 319.872 33.202 319.968 ;
      RECT 0.048 320.640 33.202 320.736 ;
      RECT 0.048 321.408 33.202 321.504 ;
      RECT 0.048 322.176 33.202 322.272 ;
      RECT 0.048 322.944 33.202 323.040 ;
      RECT 0.048 323.712 33.202 323.808 ;
      RECT 0.048 324.480 33.202 324.576 ;
      RECT 0.048 325.248 33.202 325.344 ;
      RECT 0.048 326.016 33.202 326.112 ;
      RECT 0.048 326.784 33.202 326.880 ;
      RECT 0.048 327.552 33.202 327.648 ;
      RECT 0.048 328.320 33.202 328.416 ;
      RECT 0.048 329.088 33.202 329.184 ;
      RECT 0.048 329.856 33.202 329.952 ;
      RECT 0.048 330.624 33.202 330.720 ;
      RECT 0.048 331.392 33.202 331.488 ;
    END
  END VDD
  OBS
    LAYER M1 ;
    RECT 0 0 33.250 331.800 ;
    LAYER M2 ;
    RECT 0 0 33.250 331.800 ;
    LAYER M3 ;
    RECT 0 0 33.250 331.800 ;
    LAYER M4 ;
    RECT 0 0 33.250 331.800 ;
  END
END fakeram7_sp_8192x32

END LIBRARY
